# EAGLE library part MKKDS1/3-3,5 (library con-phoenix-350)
MKKDS 1/3-3,5 Artikelnummer: 1751400 Printklemme, Nennstrom: 8 A, Nennspannung: 200 V, Rastermaß: 3,5 mm, Polzahl: 13 Anschlussart: Schraubanschluss, Montage: Löten, Anschlussrichtung Leiter/Platine: 0 °, Farbe: grün Home page

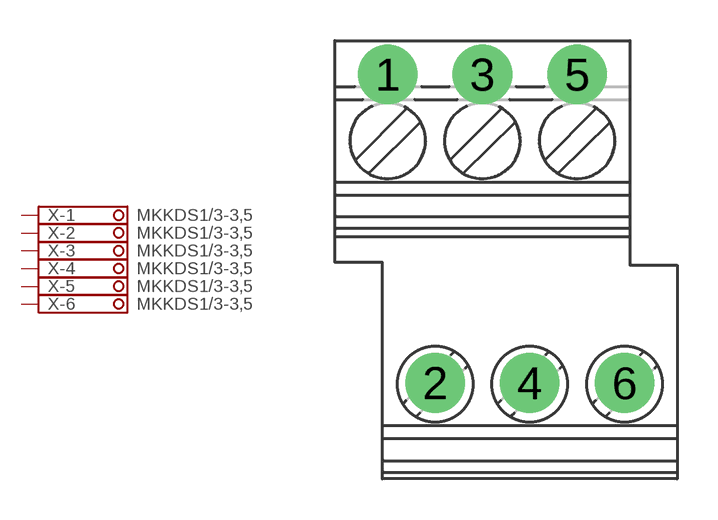
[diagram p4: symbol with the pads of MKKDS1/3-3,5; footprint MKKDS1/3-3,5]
Designator prefix X; gates -1=SCHRAUBKLEMME -2=SCHRAUBKLEMME -3=SCHRAUBKLEMME -4=SCHRAUBKLEMME -5=SCHRAUBKLEMME -6=SCHRAUBKLEMME

## MKKDS1/3-3,5  [MKKDS1/3-3,5]
1  -1:K  pas
2  -2:K  pas
3  -3:K  pas
4  -4:K  pas
5  -5:K  pas
6  -6:K  pas

## Footprint MKKDS1/3-3,5 (pad centres in mm)
MKKDS 1/3-3,5 Artikelnummer: 1751400 Printklemme, Nennstrom: 8 A, Nennspannung: 200 V, Rastermaß: 3,5 mm, Polzahl: 13 Anschlussart: Schraubanschluss, Montage: Löten, Anschlussrichtung Leiter/Platine: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
drill 1.1 pad 2.2: 1 -3.5,6.85; 2 -1.75,-4.55; 3 0,6.85; 4 1.75,-4.55; 5 3.5,6.85; 6 5.25,-4.55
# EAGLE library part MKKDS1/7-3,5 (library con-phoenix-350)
MKKDS 1/7-3,5 Artikelnummer: 1751442 Printklemme, Nennstrom: 8 A, Nennspannung: 200 V, Rastermaß: 3,5 mm, Polzahl: 13 Anschlussart: Schraubanschluss, Montage: Löten, Anschlussrichtung Leiter/Platine: 0 °, Farbe: grün Home page

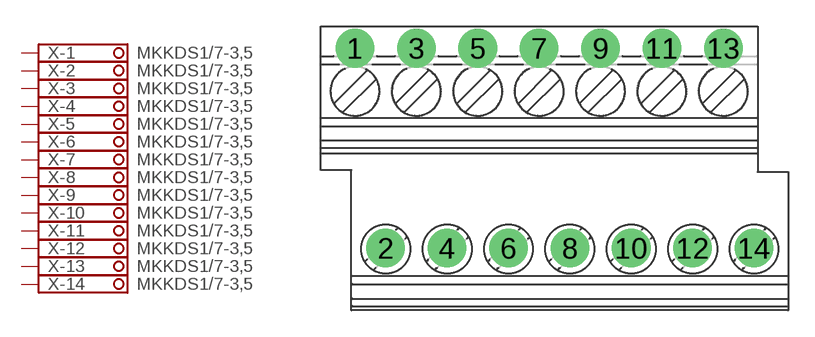
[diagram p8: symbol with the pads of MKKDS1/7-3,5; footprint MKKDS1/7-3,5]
Designator prefix X; gates -1=SCHRAUBKLEMME -2=SCHRAUBKLEMME -3=SCHRAUBKLEMME -4=SCHRAUBKLEMME -5=SCHRAUBKLEMME -6=SCHRAUBKLEMME -7=SCHRAUBKLEMME -8=SCHRAUBKLEMME -9=SCHRAUBKLEMME -10=SCHRAUBKLEMME -11=SCHRAUBKLEMME -12=SCHRAUBKLEMME -13=SCHRAUBKLEMME -14=SCHRAUBKLEMME

## MKKDS1/7-3,5  [MKKDS1/7-3,5]
1  -1:K  pas
2  -2:K  pas
3  -3:K  pas
4  -4:K  pas
5  -5:K  pas
6  -6:K  pas
7  -7:K  pas
8  -8:K  pas
9  -9:K  pas
10  -10:K  pas
11  -11:K  pas
12  -12:K  pas
13  -13:K  pas
14  -14:K  pas

## Footprint MKKDS1/7-3,5 (pad centres in mm)
MKKDS 1/7-3,5 Artikelnummer: 1751442 Printklemme, Nennstrom: 8 A, Nennspannung: 200 V, Rastermaß: 3,5 mm, Polzahl: 13 Anschlussart: Schraubanschluss, Montage: Löten, Anschlussrichtung Leiter/Platine: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
drill 1.1 pad 2.2: 1 -10.5,6.85; 2 -8.75,-4.55; 3 -7,6.85; 4 -5.25,-4.55; 5 -3.5,6.85; 6 -1.75,-4.55; 7 0,6.85; 8 1.75,-4.55; 9 3.5,6.85; 10 5.25,-4.55; 11 7,6.85; 12 8.75,-4.55; 13 10.5,6.85; 14 12.25,-4.55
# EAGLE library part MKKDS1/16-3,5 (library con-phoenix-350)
MKKDS 1/16-3,5 Artikelnummer: 1751536 Printklemme, Nennstrom: 8 A, Nennspannung: 200 V, Rastermaß: 3,5 mm, Polzahl: 13 Anschlussart: Schraubanschluss, Montage: Löten, Anschlussrichtung Leiter/Platine: 0 °, Farbe: grün Home page

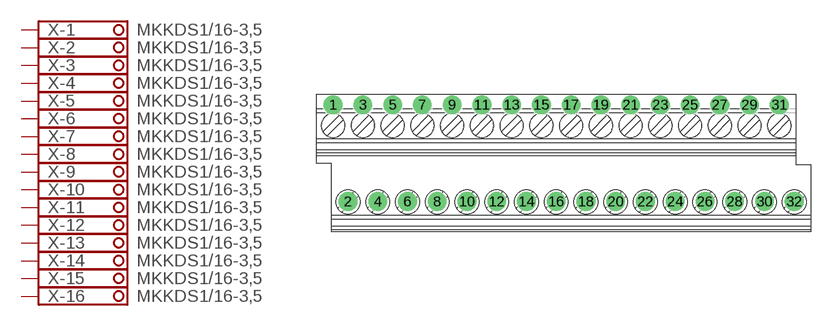
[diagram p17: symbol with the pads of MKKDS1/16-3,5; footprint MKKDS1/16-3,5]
Designator prefix X; gates -1=SCHRAUBKLEMME -2=SCHRAUBKLEMME -3=SCHRAUBKLEMME -4=SCHRAUBKLEMME -5=SCHRAUBKLEMME -6=SCHRAUBKLEMME -7=SCHRAUBKLEMME -8=SCHRAUBKLEMME -9=SCHRAUBKLEMME -10=SCHRAUBKLEMME -11=SCHRAUBKLEMME -12=SCHRAUBKLEMME -13=SCHRAUBKLEMME -14=SCHRAUBKLEMME -15=SCHRAUBKLEMME -16=SCHRAUBKLEMME -17=SCHRAUBKLEMME -18=SCHRAUBKLEMME -19=SCHRAUBKLEMME -20=SCHRAUBKLEMME -21=SCHRAUBKLEMME -22=SCHRAUBKLEMME -23=SCHRAUBKLEMME -24=SCHRAUBKLEMME -25=SCHRAUBKLEMME -26=SCHRAUBKLEMME -27=SCHRAUBKLEMME -28=SCHRAUBKLEMME -29=SCHRAUBKLEMME -30=SCHRAUBKLEMME -31=SCHRAUBKLEMME -32=SCHRAUBKLEMME

## MKKDS1/16-3,5  [MKKDS1/16-3,5]
1  -1:K  pas
2  -2:K  pas
3  -3:K  pas
4  -4:K  pas
5  -5:K  pas
6  -6:K  pas
7  -7:K  pas
8  -8:K  pas
9  -9:K  pas
10  -10:K  pas
11  -11:K  pas
12  -12:K  pas
13  -13:K  pas
14  -14:K  pas
15  -15:K  pas
16  -16:K  pas
17  -17:K  pas
18  -18:K  pas
19  -19:K  pas
20  -20:K  pas
21  -21:K  pas
22  -22:K  pas
23  -23:K  pas
24  -24:K  pas
25  -25:K  pas
26  -26:K  pas
27  -27:K  pas
28  -28:K  pas
29  -29:K  pas
30  -30:K  pas
31  -31:K  pas
32  -32:K  pas

## Footprint MKKDS1/16-3,5 (pad centres in mm)
MKKDS 1/16-3,5 Artikelnummer: 1751536 Printklemme, Nennstrom: 8 A, Nennspannung: 200 V, Rastermaß: 3,5 mm, Polzahl: 13 Anschlussart: Schraubanschluss, Montage: Löten, Anschlussrichtung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
drill 1.1 pad 2.2: 1 -26.25,6.85; 2 -24.5,-4.55; 3 -22.75,6.85; 4 -21,-4.55; 5 -19.25,6.85; 6 -17.5,-4.55; 7 -15.75,6.85; 8 -14,-4.55; 9 -12.25,6.85; 10 -10.5,-4.55; 11 -8.75,6.85; 12 -7,-4.55; 13 -5.25,6.85; 14 -3.5,-4.55; 15 -1.75,6.85; 16 0,-4.55; 17 1.75,6.85; 18 3.5,-4.55; 19 5.25,6.85; 20 7,-4.55; 21 8.75,6.85; 22 10.5,-4.55; 23 12.25,6.85; 24 14,-4.55; 25 15.75,6.85; 26 17.5,-4.55; 27 19.25,6.85; 28 21,-4.55; 29 22.75,6.85; 30 24.5,-4.55; 31 26.25,6.85; 32 28,-4.55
